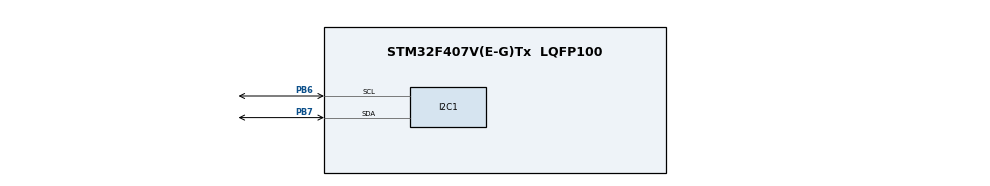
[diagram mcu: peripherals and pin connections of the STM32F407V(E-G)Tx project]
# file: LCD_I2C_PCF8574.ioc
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Mcu.Family=STM32F4
Mcu.Name=STM32F407V(E-G)Tx
Mcu.Package=LQFP100
NVIC.PriorityGroup=NVIC_PRIORITYGROUP_4
PB6.Mode=I2C
PB6.Signal=I2C1_SCL
PB7.Mode=I2C
PB7.Signal=I2C1_SDA
ProjectManager.HeapSize=0x200
ProjectManager.StackSize=0x400
ProjectManager.TargetToolchain=STM32CubeIDE
RCC.AHBFreq_Value=16000000
RCC.APB1Freq_Value=16000000
RCC.APB2Freq_Value=16000000
RCC.CortexFreq_Value=16000000
RCC.HSE_VALUE=25000000
RCC.HSI_VALUE=16000000
RCC.LSE_VALUE=32768
RCC.SYSCLKFreq_VALUE=16000000
RCC.VCOOutputFreq_Value=192000000
board=custom

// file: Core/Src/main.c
/* USER CODE BEGIN Header */
/**
  ******************************************************************************
  * @file           : main.c
  * @brief          : Main program body
  ******************************************************************************
  * @attention
  *
  * Copyright (c) 2025 STMicroelectronics.
  * All rights reserved.
  *
  * This software is licensed under terms that can be found in the LICENSE file
  * in the root directory of this software component.
  * If no LICENSE file comes with this software, it is provided AS-IS.
  *
  ******************************************************************************
  */
/* USER CODE END Header */
#include "main.h"

/* USER CODE BEGIN Includes */
#include"lcd_i2c.h"
/* USER CODE END Includes */

I2C_HandleTypeDef hi2c1;

void SystemClock_Config(void);
static void MX_GPIO_Init(void);
static void MX_I2C1_Init(void);

int main(void)
{

  /* USER CODE BEGIN 1 */
	//int var;

  /* USER CODE END 1 */

  /* MCU Configuration--------------------------------------------------------*/

  /* Reset of all peripherals, Initializes the Flash interface and the Systick. */
  HAL_Init();

  /* Configure the system clock */
  SystemClock_Config();

  /* Initialize all configured peripherals */
  MX_GPIO_Init();
  MX_I2C1_Init();

  /* Infinite loop */
  /* USER CODE BEGIN WHILE */

  LCD_Init(&hi2c1);
// 	  LCD_Set_Cursor(1,0);
// 	  LCD_Send_Integer(123453456);
// 	  HAL_Delay(500);

//  LCD_Set_Cursor(1,0);
//  LCD_Send_Float(123.23,2);
  LCD_Set_Cursor(0,0);

  LCD_Send_Cmd(0x18); // Shift entire display left

  //LCD_Send_Cmd(0x1C); // Shift entire display right

  while (1)
  {

    /* USER CODE END WHILE */

    /* USER CODE BEGIN 3 */
//	  var=HAL_GPIO_ReadPin(GPIOA, GPIO_PIN_7);
//	  LCD_Send_Cmd(0x01);
//	  HAL_Delay(

	  LCD_Send_Integer(123);
	  HAL_Delay(1000);
	  LCD_Send_Cmd(0x01);
	  //LCD_Clear();
//	  LCD_Send_String("Loginware");
//	  HAL_Delay(2000);
//	  LCD_Clear();

//	  HAL_Delay(500);
//	  LCD_Set_Cursor(1,0);
//	  LCD_Send_String("kencha");
//	  HAL_Delay(500);
  }
  /* USER CODE END 3 */
}

void SystemClock_Config(void)
{
  RCC_OscInitTypeDef RCC_OscInitStruct = {0};
  RCC_ClkInitTypeDef RCC_ClkInitStruct = {0};

  /** Configure the main internal regulator output voltage
  */
  __HAL_RCC_PWR_CLK_ENABLE();
  __HAL_PWR_VOLTAGESCALING_CONFIG(PWR_REGULATOR_VOLTAGE_SCALE2);

  /** Initializes the RCC Oscillators according to the specified parameters
  * in the RCC_OscInitTypeDef structure.
  */
  RCC_OscInitStruct.OscillatorType = RCC_OSCILLATORTYPE_HSI;
  RCC_OscInitStruct.HSIState = RCC_HSI_ON;
  RCC_OscInitStruct.HSICalibrationValue = RCC_HSICALIBRATION_DEFAULT;
  RCC_OscInitStruct.PLL.PLLState = RCC_PLL_ON;
  RCC_OscInitStruct.PLL.PLLSource = RCC_PLLSOURCE_HSI;
  RCC_OscInitStruct.PLL.PLLM = 16;
  RCC_OscInitStruct.PLL.PLLN = 336;
  RCC_OscInitStruct.PLL.PLLP = RCC_PLLP_DIV4;
  RCC_OscInitStruct.PLL.PLLQ = 7;
  if (HAL_RCC_OscConfig(&RCC_OscInitStruct) != HAL_OK)
  {
    Error_Handler();
  }

  /** Initializes the CPU, AHB and APB buses clocks
  */
  RCC_ClkInitStruct.ClockType = RCC_CLOCKTYPE_HCLK|RCC_CLOCKTYPE_SYSCLK
                              |RCC_CLOCKTYPE_PCLK1|RCC_CLOCKTYPE_PCLK2;
  RCC_ClkInitStruct.SYSCLKSource = RCC_SYSCLKSOURCE_PLLCLK;
  RCC_ClkInitStruct.AHBCLKDivider = RCC_SYSCLK_DIV1;
  RCC_ClkInitStruct.APB1CLKDivider = RCC_HCLK_DIV2;
  RCC_ClkInitStruct.APB2CLKDivider = RCC_HCLK_DIV1;

  if (HAL_RCC_ClockConfig(&RCC_ClkInitStruct, FLASH_LATENCY_2) != HAL_OK)
  {
    Error_Handler();
  }
}

static void MX_I2C1_Init(void)
{

  hi2c1.Instance = I2C1;
  hi2c1.Init.ClockSpeed = 100000;
  hi2c1.Init.DutyCycle = I2C_DUTYCYCLE_2;
  hi2c1.Init.OwnAddress1 = 0;
  hi2c1.Init.AddressingMode = I2C_ADDRESSINGMODE_7BIT;
  hi2c1.Init.DualAddressMode = I2C_DUALADDRESS_DISABLE;
  hi2c1.Init.OwnAddress2 = 0;
  hi2c1.Init.GeneralCallMode = I2C_GENERALCALL_DISABLE;
  hi2c1.Init.NoStretchMode = I2C_NOSTRETCH_DISABLE;
  if (HAL_I2C_Init(&hi2c1) != HAL_OK)
  {
    Error_Handler();
  }

}

static void MX_GPIO_Init(void)
{
  GPIO_InitTypeDef GPIO_InitStruct = {0};

  /* GPIO Ports Clock Enable */
  __HAL_RCC_GPIOA_CLK_ENABLE();
  __HAL_RCC_GPIOB_CLK_ENABLE();

  /*Configure GPIO pin : PA7 */
  GPIO_InitStruct.Pin = GPIO_PIN_7;
  GPIO_InitStruct.Mode = GPIO_MODE_INPUT;
  GPIO_InitStruct.Pull = GPIO_PULLDOWN;
  HAL_GPIO_Init(GPIOA, &GPIO_InitStruct);

}

void Error_Handler(void)
{
  __disable_irq();
  while (1)
  {
  }
}
